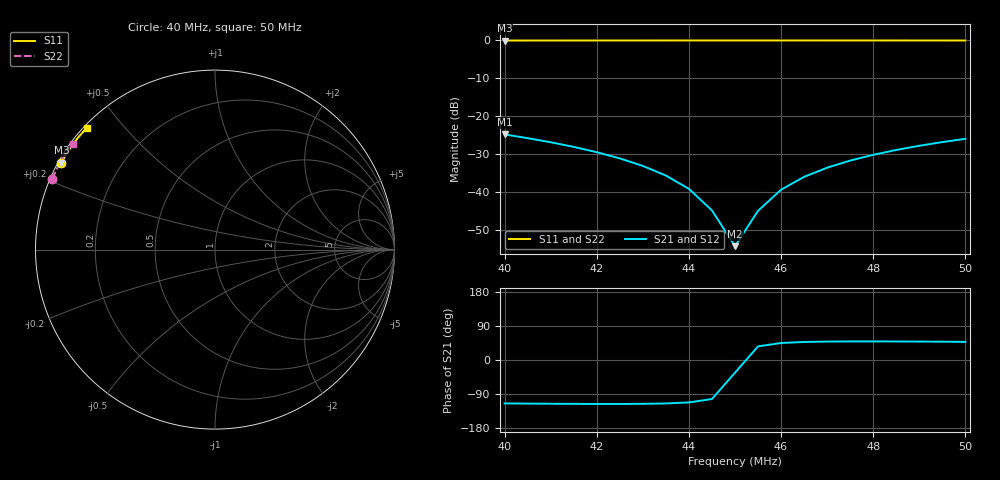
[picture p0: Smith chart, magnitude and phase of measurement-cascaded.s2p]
! Parameter plane de-embed bench export
! Network: measurement-cascaded
! PortZ0: 50+0j 50+0j
# mhz S RI R 50
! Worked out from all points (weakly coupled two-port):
!   21 points, 40 MHz to 50 MHz, reference 50 ohm
!   highest |S21| = -24.90 dB at 40 MHz (marker M1); lowest = -54.3 dB at 45 MHz (marker M2)
!   lowest |S11| = -0.1 dB at 40 MHz (marker M3), VSWR 118.71, Z = 0.45 + j13.2 ohm
!   |S11| at or under -10 dB: nowhere
!   |S22| runs from -0.1 to -0.1 dB; largest |S21 - S12| = 1e-13
40  -0.8555 0.4847  -0.0236 -0.0518  -0.0236 -0.0518  -0.9054 0.3951
40.5  -0.8494 0.4959  -0.0215 -0.0461  -0.0215 -0.0461  -0.901 0.4062
41  -0.8432 0.5069  -0.0193 -0.0405  -0.0193 -0.0405  -0.8964 0.4172
41.5  -0.8369 0.5177  -0.017 -0.0351  -0.017 -0.0351  -0.8914 0.4279
42  -0.8304 0.5283  -0.0146 -0.0299  -0.0146 -0.0299  -0.8864 0.4385
42.5  -0.8239 0.5388  -0.0121 -0.0247  -0.0121 -0.0247  -0.8812 0.449
43  -0.8172 0.5492  -0.00948 -0.0197  -0.00948 -0.0197  -0.8759 0.4593
43.5  -0.8105 0.5593  -0.00682 -0.0149  -0.00682 -0.0149  -0.8705 0.4694
44  -0.8037 0.5693  -0.00408 -0.0101  -0.00408 -0.0101  -0.865 0.4795
44.5  -0.7968 0.5791  -0.00127 -0.00553  -0.00127 -0.00553  -0.8594 0.4894
45  -0.7898 0.5888  0.0016 -0.00106  0.0016 -0.00106  -0.8537 0.4992
45.5  -0.7828 0.5983  0.00454 0.00329  0.00454 0.00329  -0.848 0.5088
46  -0.7756 0.6077  0.00755 0.00751  0.00755 0.00751  -0.8421 0.5183
46.5  -0.7684 0.6169  0.0106 0.0116  0.0106 0.0116  -0.8362 0.5277
47  -0.761 0.6258  0.0137 0.0156  0.0137 0.0156  -0.8302 0.537
47.5  -0.7535 0.6346  0.0169 0.0194  0.0169 0.0194  -0.8241 0.5462
48  -0.7459 0.6432  0.0201 0.0232  0.0201 0.0232  -0.818 0.5552
48.5  -0.7382 0.6516  0.0234 0.0268  0.0234 0.0268  -0.8117 0.5641
49  -0.7306 0.6599  0.0267 0.0303  0.0267 0.0303  -0.8054 0.5729
49.5  -0.7228 0.6681  0.03 0.0337  0.03 0.0337  -0.7991 0.5816
50  -0.715 0.6761  0.0334 0.037  0.0334 0.037  -0.7927 0.5902
